One B-rep face of a CAD part: STEP entity #1415.
In plain terms, the planar face has unit normal (1, 0, 0).
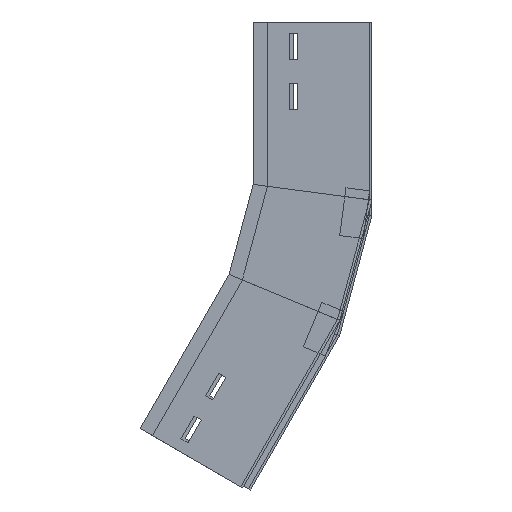
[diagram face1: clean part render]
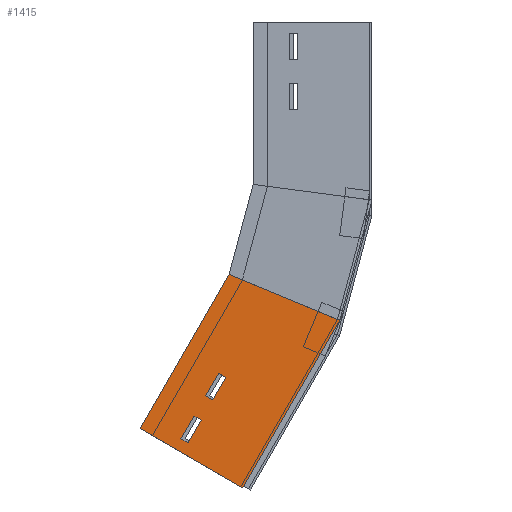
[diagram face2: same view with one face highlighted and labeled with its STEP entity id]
Its self-contained STEP definition (entity closure, numbers rounded to 3 decimals):
#22 = LINE ( 'NONE', #501, #1003 ) ;
#27 = DIRECTION ( 'NONE',  ( 0., -1., 0. ) ) ;
#28 = VERTEX_POINT ( 'NONE', #1115 ) ;
#30 = CARTESIAN_POINT ( 'NONE',  ( 0., 59., -31.835 ) ) ;
#34 = ORIENTED_EDGE ( 'NONE', *, *, #581, .T. ) ;
#45 = LINE ( 'NONE', #284, #545 ) ;
#82 = CARTESIAN_POINT ( 'NONE',  ( 0., 21.094, -160.223 ) ) ;
#90 = CARTESIAN_POINT ( 'NONE',  ( 0., 66., -9.835 ) ) ;
#98 = CARTESIAN_POINT ( 'NONE',  ( 0., 66., -73.505 ) ) ;
#99 = EDGE_CURVE ( 'NONE', #630, #1129, #347, .T. ) ;
#125 = ORIENTED_EDGE ( 'NONE', *, *, #757, .T. ) ;
#130 = DIRECTION ( 'NONE',  ( -1., 0., 0. ) ) ;
#131 = CARTESIAN_POINT ( 'NONE',  ( 0., 100., 0. ) ) ;
#142 = ORIENTED_EDGE ( 'NONE', *, *, #408, .T. ) ;
#168 = EDGE_CURVE ( 'NONE', #1129, #351, #564, .T. ) ;
#174 = VECTOR ( 'NONE', #678, 1000. ) ;
#177 = EDGE_LOOP ( 'NONE', ( #702, #34, #1395, #125 ) ) ;
#191 = ORIENTED_EDGE ( 'NONE', *, *, #1112, .T. ) ;
#200 = LINE ( 'NONE', #440, #174 ) ;
#220 = EDGE_LOOP ( 'NONE', ( #500, #502, #142, #1055 ) ) ;
#251 = CARTESIAN_POINT ( 'NONE',  ( 0., 66., -51.505 ) ) ;
#269 = EDGE_CURVE ( 'NONE', #530, #1052, #45, .T. ) ;
#272 = VERTEX_POINT ( 'NONE', #965 ) ;
#284 = CARTESIAN_POINT ( 'NONE',  ( 0., 66., -51.505 ) ) ;
#344 = EDGE_CURVE ( 'NONE', #346, #272, #1140, .T. ) ;
#346 = VERTEX_POINT ( 'NONE', #906 ) ;
#347 = LINE ( 'NONE', #797, #582 ) ;
#349 = DIRECTION ( 'NONE',  ( 0., 0., 1. ) ) ;
#351 = VERTEX_POINT ( 'NONE', #563 ) ;
#358 = FACE_OUTER_BOUND ( 'NONE', #220, .T. ) ;
#359 = DIRECTION ( 'NONE',  ( 0., 0., -1. ) ) ;
#381 = CARTESIAN_POINT ( 'NONE',  ( 0., 66., -9.835 ) ) ;
#387 = EDGE_CURVE ( 'NONE', #918, #960, #1130, .T. ) ;
#389 = VECTOR ( 'NONE', #727, 1000. ) ;
#399 = CARTESIAN_POINT ( 'NONE',  ( 0., 66., -9.835 ) ) ;
#408 = EDGE_CURVE ( 'NONE', #509, #351, #1257, .T. ) ;
#412 = LINE ( 'NONE', #616, #946 ) ;
#431 = VECTOR ( 'NONE', #359, 1000. ) ;
#435 = ORIENTED_EDGE ( 'NONE', *, *, #1132, .T. ) ;
#440 = CARTESIAN_POINT ( 'NONE',  ( 0., 59., -51.505 ) ) ;
#474 = PLANE ( 'NONE',  #1288 ) ;
#483 = DIRECTION ( 'NONE',  ( 0., 0., -1. ) ) ;
#500 = ORIENTED_EDGE ( 'NONE', *, *, #99, .F. ) ;
#501 = CARTESIAN_POINT ( 'NONE',  ( 0., 59., -9.835 ) ) ;
#502 = ORIENTED_EDGE ( 'NONE', *, *, #1241, .F. ) ;
#505 = VECTOR ( 'NONE', #27, 1000. ) ;
#509 = VERTEX_POINT ( 'NONE', #572 ) ;
#530 = VERTEX_POINT ( 'NONE', #944 ) ;
#539 = VERTEX_POINT ( 'NONE', #30 ) ;
#545 = VECTOR ( 'NONE', #628, 1000. ) ;
#563 = CARTESIAN_POINT ( 'NONE',  ( 0., 0., -163. ) ) ;
#564 = LINE ( 'NONE', #82, #1155 ) ;
#571 = EDGE_CURVE ( 'NONE', #28, #918, #606, .T. ) ;
#572 = CARTESIAN_POINT ( 'NONE',  ( 0., 0., 0. ) ) ;
#581 = EDGE_CURVE ( 'NONE', #1052, #346, #1064, .T. ) ;
#582 = VECTOR ( 'NONE', #1263, 1000. ) ;
#595 = CARTESIAN_POINT ( 'NONE',  ( 0., 66., -31.835 ) ) ;
#603 = CARTESIAN_POINT ( 'NONE',  ( 0., 100., -149.835 ) ) ;
#606 = LINE ( 'NONE', #399, #389 ) ;
#616 = CARTESIAN_POINT ( 'NONE',  ( 0., 0., 0. ) ) ;
#628 = DIRECTION ( 'NONE',  ( 0., 1., 0. ) ) ;
#630 = VERTEX_POINT ( 'NONE', #131 ) ;
#678 = DIRECTION ( 'NONE',  ( 0., 0., 1. ) ) ;
#682 = DIRECTION ( 'NONE',  ( 0., -1., 0. ) ) ;
#702 = ORIENTED_EDGE ( 'NONE', *, *, #269, .T. ) ;
#727 = DIRECTION ( 'NONE',  ( 0., 1., 0. ) ) ;
#737 = DIRECTION ( 'NONE',  ( 0., 1., 0. ) ) ;
#757 = EDGE_CURVE ( 'NONE', #272, #530, #200, .T. ) ;
#792 = FACE_BOUND ( 'NONE', #1150, .T. ) ;
#797 = CARTESIAN_POINT ( 'NONE',  ( 0., 100., 0. ) ) ;
#836 = VECTOR ( 'NONE', #922, 1000. ) ;
#839 = CARTESIAN_POINT ( 'NONE',  ( 0., 66., -31.835 ) ) ;
#906 = CARTESIAN_POINT ( 'NONE',  ( 0., 66., -73.505 ) ) ;
#918 = VERTEX_POINT ( 'NONE', #381 ) ;
#922 = DIRECTION ( 'NONE',  ( 0., 0., -1. ) ) ;
#944 = CARTESIAN_POINT ( 'NONE',  ( 0., 59., -51.505 ) ) ;
#946 = VECTOR ( 'NONE', #737, 1000. ) ;
#952 = DIRECTION ( 'NONE',  ( 0., 0., 1. ) ) ;
#960 = VERTEX_POINT ( 'NONE', #595 ) ;
#965 = CARTESIAN_POINT ( 'NONE',  ( 0., 59., -73.505 ) ) ;
#979 = ORIENTED_EDGE ( 'NONE', *, *, #387, .T. ) ;
#1003 = VECTOR ( 'NONE', #952, 1000. ) ;
#1010 = CARTESIAN_POINT ( 'NONE',  ( 0., 0., 0. ) ) ;
#1043 = CARTESIAN_POINT ( 'NONE',  ( 0., 0., 0. ) ) ;
#1052 = VERTEX_POINT ( 'NONE', #1338 ) ;
#1055 = ORIENTED_EDGE ( 'NONE', *, *, #168, .F. ) ;
#1061 = LINE ( 'NONE', #839, #505 ) ;
#1064 = LINE ( 'NONE', #251, #1487 ) ;
#1112 = EDGE_CURVE ( 'NONE', #960, #539, #1061, .T. ) ;
#1115 = CARTESIAN_POINT ( 'NONE',  ( 0., 59., -9.835 ) ) ;
#1129 = VERTEX_POINT ( 'NONE', #603 ) ;
#1130 = LINE ( 'NONE', #90, #836 ) ;
#1132 = EDGE_CURVE ( 'NONE', #539, #28, #22, .T. ) ;
#1140 = LINE ( 'NONE', #98, #1383 ) ;
#1150 = EDGE_LOOP ( 'NONE', ( #1289, #979, #191, #435 ) ) ;
#1155 = VECTOR ( 'NONE', #1269, 1000. ) ;
#1241 = EDGE_CURVE ( 'NONE', #509, #630, #412, .T. ) ;
#1257 = LINE ( 'NONE', #1010, #431 ) ;
#1263 = DIRECTION ( 'NONE',  ( 0., 0., -1. ) ) ;
#1269 = DIRECTION ( 'NONE',  ( 0., -0.991, -0.131 ) ) ;
#1288 = AXIS2_PLACEMENT_3D ( 'NONE', #1043, #130, #349 ) ;
#1289 = ORIENTED_EDGE ( 'NONE', *, *, #571, .T. ) ;
#1338 = CARTESIAN_POINT ( 'NONE',  ( 0., 66., -51.505 ) ) ;
#1357 = FACE_BOUND ( 'NONE', #177, .T. ) ;
#1383 = VECTOR ( 'NONE', #682, 1000. ) ;
#1395 = ORIENTED_EDGE ( 'NONE', *, *, #344, .T. ) ;
#1415 = ADVANCED_FACE ( 'NONE', ( #1357, #358, #792 ), #474, .F. ) ;
#1487 = VECTOR ( 'NONE', #483, 1000. ) ;
